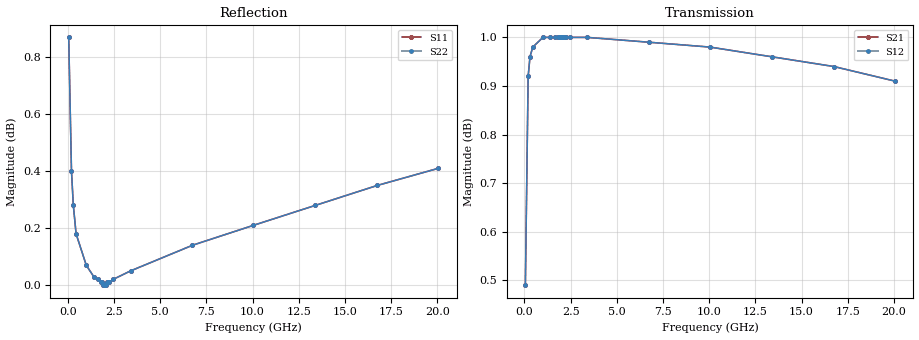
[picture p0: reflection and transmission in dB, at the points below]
! AVX Thin Film Operation		Date: may 2004
! Description: Accu-P® Series, Thin Film, SMD, RF Capacitor
! Part Number: 0201ZK180JBW
! 50 MHz  -  10.05 GHz
! Serial Measurements
# mhz S db R 50
!	S11		S21		S12		S22
!	dB	Phase	dB	Phase	dB	Phase	dB	Phase
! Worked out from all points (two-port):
!   401 points, 50 MHz to 20.05 GHz, reference 50 ohm
!   highest |S21| = 1.00 dB at 1.65 GHz (marker M1); lowest = 0.5 dB at 50 MHz (marker M2)
!   |S21| within 3 dB of the highest: start of sweep to end of sweep
!   lowest |S11| = 0.0 dB at 2 GHz (marker M3)
!   |S11| at or under -10 dB: nowhere
!   |S22| runs from 0.0 to 0.9 dB; largest |S21 - S12| = 0
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50  0.87 -29.5  0.49 60.5  0.49 60.5  0.87 -29.5
200  0.40 -66.2  0.92 23.6  0.92 23.6  0.40 -66.2
300  0.28 -73.7  0.96 16.0  0.96 16.0  0.28 -73.7
450  0.18 -79.0  0.98 10.5  0.98 10.5  0.18 -79.0
1000  0.07 -84.9  1.00 3.8  1.00 3.8  0.07 -84.9
1400  0.03 -85.4  1.00 1.8  1.00 1.8  0.03 -85.4
1650  0.02 -83.6  1.00 0.9  1.00 0.9  0.02 -83.6
1800  0.01 -79.1  1.00 0.5  1.00 0.5  0.01 -79.1
1850  0.01 -75.1  1.00 0.3  1.00 0.3  0.01 -75.1
1900  0.00 -66.3  1.00 0.2  1.00 0.2  0.00 -66.3
2000  0.00 33.5  1.00 -0.1  1.00 -0.1  0.00 33.5
2050  0.00 64.2  1.00 -0.2  1.00 -0.2  0.00 64.2
2100  0.01 73.7  1.00 -0.3  1.00 -0.3  0.01 73.7
2150  0.01 77.9  1.00 -0.4  1.00 -0.4  0.01 77.9
2250  0.01 81.7  1.00 -0.7  1.00 -0.7  0.01 81.7
2450  0.02 84.3  1.00 -1.1  1.00 -1.1  0.02 84.3
3400  0.05 85.3  1.00 -2.9  1.00 -2.9  0.05 85.3
6750  0.14 81.4  0.99 -7.9  0.99 -7.9  0.14 81.4
10050  0.21 77.3  0.98 -12.3  0.98 -12.3  0.21 77.3
13400  0.28 73.2  0.96 -16.5  0.96 -16.5  0.28 73.2
16750  0.35 69.3  0.94 -20.5  0.94 -20.5  0.35 69.3
20050  0.41 65.7  0.91 -24.2  0.91 -24.2  0.41 65.7
